VERSION 5.7 ;
  NOWIREEXTENSIONATPIN ON ;
  DIVIDERCHAR "/" ;
  BUSBITCHARS "[]" ;
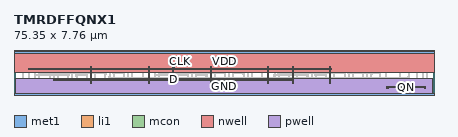
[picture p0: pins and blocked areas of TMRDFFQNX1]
MACRO TMRDFFQNX1
  CLASS CORE ;
  FOREIGN TMRDFFQNX1 ;
  ORIGIN 0.000 0.000 ;
  SIZE 75.350 BY 7.760 ;
  SYMMETRY X Y ;
  SITE unitrh ;
  PIN QN
    DIRECTION OUTPUT ;
    USE SIGNAL ;
    ANTENNADIFFAREA 1.734950 ;
    PORT
      LAYER met1 ;
        RECT 66.905 1.445 67.135 1.475 ;
        RECT 70.235 1.445 70.465 1.475 ;
        RECT 73.565 1.445 73.795 1.475 ;
        RECT 66.875 1.275 73.825 1.445 ;
        RECT 66.905 1.245 67.135 1.275 ;
        RECT 70.235 1.245 70.465 1.275 ;
        RECT 73.565 1.245 73.795 1.275 ;
    END
  END QN
  PIN D
    DIRECTION INPUT ;
    USE SIGNAL ;
    ANTENNAGATEAREA 3.081750 ;
    PORT
      LAYER met1 ;
        RECT 7.035 2.855 7.265 2.885 ;
        RECT 28.495 2.855 28.725 2.885 ;
        RECT 49.955 2.855 50.185 2.885 ;
        RECT 7.005 2.685 50.215 2.855 ;
        RECT 7.035 2.655 7.265 2.685 ;
        RECT 28.495 2.655 28.725 2.685 ;
        RECT 49.955 2.655 50.185 2.685 ;
    END
    PORT
      LAYER li1 ;
        RECT 28.555 4.890 28.725 5.045 ;
        RECT 28.525 4.715 28.725 4.890 ;
        RECT 28.525 2.095 28.695 4.715 ;
      LAYER mcon ;
        RECT 28.525 2.685 28.695 2.855 ;
    END
    PORT
      LAYER li1 ;
        RECT 50.015 4.890 50.185 5.045 ;
        RECT 49.985 4.715 50.185 4.890 ;
        RECT 49.985 2.095 50.155 4.715 ;
      LAYER mcon ;
        RECT 49.985 2.685 50.155 2.855 ;
    END
  END D
  PIN CLK
    DIRECTION INPUT ;
    USE SIGNAL ;
    ANTENNAGATEAREA 6.126300 ;
    PORT
      LAYER met1 ;
        RECT 2.595 4.705 2.825 4.735 ;
        RECT 13.695 4.705 13.925 4.735 ;
        RECT 24.055 4.705 24.285 4.735 ;
        RECT 35.155 4.705 35.385 4.735 ;
        RECT 45.515 4.705 45.745 4.735 ;
        RECT 56.615 4.705 56.845 4.735 ;
        RECT 2.565 4.700 13.955 4.705 ;
        RECT 17.235 4.700 56.875 4.705 ;
        RECT 2.565 4.545 56.875 4.700 ;
        RECT 2.565 4.535 13.955 4.545 ;
        RECT 17.235 4.535 56.875 4.545 ;
        RECT 2.595 4.505 2.825 4.535 ;
        RECT 13.695 4.505 13.925 4.535 ;
        RECT 24.055 4.505 24.285 4.535 ;
        RECT 35.155 4.505 35.385 4.535 ;
        RECT 45.515 4.505 45.745 4.535 ;
        RECT 56.615 4.505 56.845 4.535 ;
    END
    PORT
      LAYER li1 ;
        RECT 13.755 4.890 13.925 5.045 ;
        RECT 13.725 4.715 13.925 4.890 ;
        RECT 13.725 2.095 13.895 4.715 ;
      LAYER mcon ;
        RECT 13.725 4.535 13.895 4.705 ;
    END
    PORT
      LAYER li1 ;
        RECT 24.085 2.095 24.255 5.045 ;
      LAYER mcon ;
        RECT 24.085 4.535 24.255 4.705 ;
    END
    PORT
      LAYER li1 ;
        RECT 35.215 4.890 35.385 5.045 ;
        RECT 35.185 4.715 35.385 4.890 ;
        RECT 35.185 2.095 35.355 4.715 ;
      LAYER mcon ;
        RECT 35.185 4.535 35.355 4.705 ;
    END
    PORT
      LAYER li1 ;
        RECT 45.545 2.095 45.715 5.045 ;
      LAYER mcon ;
        RECT 45.545 4.535 45.715 4.705 ;
    END
    PORT
      LAYER li1 ;
        RECT 56.675 4.890 56.845 5.045 ;
        RECT 56.645 4.715 56.845 4.890 ;
        RECT 56.645 2.095 56.815 4.715 ;
      LAYER mcon ;
        RECT 56.645 4.535 56.815 4.705 ;
    END
  END CLK
  PIN VDD
    DIRECTION INOUT ;
    USE POWER ;
    SHAPE ABUTMENT ;
    PORT
      LAYER nwell ;
        RECT 0.000 4.110 75.350 7.940 ;
      LAYER met1 ;
        RECT 0.000 7.410 75.350 7.760 ;
    END
  END VDD
  PIN GND
    DIRECTION INOUT ;
    USE POWER ;
    SHAPE ABUTMENT ;
    PORT
      LAYER pwell ;
        RECT 0.320 0.000 75.030 2.900 ;
      LAYER met1 ;
        RECT 0.000 0.000 75.350 0.350 ;
    END
  END GND
  OBS
      LAYER li1 ;
        RECT 0.000 7.410 75.350 7.760 ;
        RECT 0.320 4.290 0.660 7.410 ;
        RECT 1.495 5.395 1.665 7.410 ;
        RECT 1.935 5.420 2.105 7.200 ;
        RECT 2.375 5.735 2.545 7.410 ;
        RECT 2.815 5.420 2.985 7.200 ;
        RECT 3.255 5.735 3.425 7.410 ;
        RECT 3.695 5.420 3.865 7.200 ;
        RECT 4.135 5.735 4.305 7.410 ;
        RECT 1.935 5.250 4.645 5.420 ;
        RECT 0.320 0.350 0.660 2.900 ;
        RECT 1.515 2.095 1.685 5.045 ;
        RECT 2.625 2.095 2.795 5.045 ;
        RECT 3.735 2.095 3.905 5.045 ;
        RECT 0.995 1.855 1.165 1.935 ;
        RECT 1.965 1.855 2.135 1.935 ;
        RECT 2.935 1.855 3.105 1.935 ;
        RECT 0.995 1.685 3.105 1.855 ;
        RECT 0.995 0.555 1.165 1.685 ;
        RECT 1.480 0.350 1.650 1.310 ;
        RECT 1.965 0.805 2.135 1.685 ;
        RECT 2.935 1.605 3.105 1.685 ;
        RECT 2.455 1.260 2.625 1.340 ;
        RECT 3.505 1.260 3.675 1.935 ;
        RECT 4.475 1.930 4.645 5.250 ;
        RECT 5.130 4.290 5.470 7.410 ;
        RECT 6.005 5.315 6.175 7.410 ;
        RECT 6.445 5.465 6.615 7.200 ;
        RECT 6.885 5.735 7.055 7.410 ;
        RECT 7.325 5.465 7.495 7.200 ;
        RECT 7.765 5.735 7.935 7.410 ;
        RECT 6.445 5.295 7.975 5.465 ;
        RECT 2.455 1.090 3.675 1.260 ;
        RECT 2.455 1.010 2.625 1.090 ;
        RECT 2.935 0.805 3.105 0.885 ;
        RECT 1.965 0.635 3.105 0.805 ;
        RECT 1.965 0.555 2.135 0.635 ;
        RECT 2.935 0.555 3.105 0.635 ;
        RECT 3.505 0.805 3.675 1.090 ;
        RECT 3.990 1.760 4.645 1.930 ;
        RECT 3.990 1.025 4.160 1.760 ;
        RECT 4.475 0.805 4.645 1.575 ;
        RECT 3.505 0.635 4.645 0.805 ;
        RECT 3.505 0.555 3.675 0.635 ;
        RECT 4.475 0.555 4.645 0.635 ;
        RECT 5.130 0.350 5.470 2.900 ;
        RECT 6.325 2.095 6.495 5.045 ;
        RECT 7.095 4.890 7.265 5.045 ;
        RECT 7.065 4.715 7.265 4.890 ;
        RECT 7.065 2.095 7.235 4.715 ;
        RECT 5.910 1.845 6.080 1.925 ;
        RECT 6.880 1.845 7.050 1.925 ;
        RECT 7.805 1.920 7.975 5.295 ;
        RECT 8.460 4.290 8.800 7.410 ;
        RECT 9.335 5.315 9.505 7.410 ;
        RECT 9.775 5.465 9.945 7.200 ;
        RECT 10.215 5.735 10.385 7.410 ;
        RECT 10.655 5.465 10.825 7.200 ;
        RECT 11.095 5.735 11.265 7.410 ;
        RECT 9.775 5.295 11.305 5.465 ;
        RECT 5.910 1.675 7.050 1.845 ;
        RECT 5.910 0.545 6.080 1.675 ;
        RECT 6.395 0.350 6.565 1.300 ;
        RECT 6.880 0.795 7.050 1.675 ;
        RECT 7.365 1.750 7.975 1.920 ;
        RECT 7.365 1.015 7.535 1.750 ;
        RECT 7.850 0.795 8.020 1.565 ;
        RECT 6.880 0.625 8.020 0.795 ;
        RECT 6.880 0.545 7.050 0.625 ;
        RECT 7.850 0.545 8.020 0.625 ;
        RECT 8.460 0.350 8.800 2.900 ;
        RECT 9.655 2.095 9.825 5.045 ;
        RECT 10.425 4.890 10.595 5.045 ;
        RECT 10.395 4.715 10.595 4.890 ;
        RECT 10.395 2.095 10.565 4.715 ;
        RECT 9.240 1.845 9.410 1.925 ;
        RECT 10.210 1.845 10.380 1.925 ;
        RECT 11.135 1.920 11.305 5.295 ;
        RECT 11.790 4.290 12.130 7.410 ;
        RECT 12.665 5.315 12.835 7.410 ;
        RECT 13.105 5.465 13.275 7.200 ;
        RECT 13.545 5.735 13.715 7.410 ;
        RECT 13.985 5.465 14.155 7.200 ;
        RECT 14.425 5.735 14.595 7.410 ;
        RECT 13.105 5.295 14.635 5.465 ;
        RECT 9.240 1.675 10.380 1.845 ;
        RECT 9.240 0.545 9.410 1.675 ;
        RECT 9.725 0.350 9.895 1.300 ;
        RECT 10.210 0.795 10.380 1.675 ;
        RECT 10.695 1.750 11.305 1.920 ;
        RECT 10.695 1.015 10.865 1.750 ;
        RECT 11.180 0.795 11.350 1.565 ;
        RECT 10.210 0.625 11.350 0.795 ;
        RECT 10.210 0.545 10.380 0.625 ;
        RECT 11.180 0.545 11.350 0.625 ;
        RECT 11.790 0.350 12.130 2.900 ;
        RECT 12.985 2.095 13.155 5.045 ;
        RECT 12.570 1.845 12.740 1.925 ;
        RECT 13.540 1.845 13.710 1.925 ;
        RECT 14.465 1.920 14.635 5.295 ;
        RECT 15.120 4.290 15.460 7.410 ;
        RECT 15.995 5.315 16.165 7.410 ;
        RECT 16.435 5.465 16.605 7.200 ;
        RECT 16.875 5.735 17.045 7.410 ;
        RECT 17.315 5.465 17.485 7.200 ;
        RECT 17.755 5.735 17.925 7.410 ;
        RECT 16.435 5.295 17.965 5.465 ;
        RECT 12.570 1.675 13.710 1.845 ;
        RECT 12.570 0.545 12.740 1.675 ;
        RECT 13.055 0.350 13.225 1.300 ;
        RECT 13.540 0.795 13.710 1.675 ;
        RECT 14.025 1.750 14.635 1.920 ;
        RECT 14.025 1.015 14.195 1.750 ;
        RECT 14.510 0.795 14.680 1.565 ;
        RECT 13.540 0.625 14.680 0.795 ;
        RECT 13.540 0.545 13.710 0.625 ;
        RECT 14.510 0.545 14.680 0.625 ;
        RECT 15.120 0.350 15.460 2.900 ;
        RECT 16.315 2.095 16.485 5.045 ;
        RECT 17.085 4.890 17.255 5.045 ;
        RECT 17.055 4.715 17.255 4.890 ;
        RECT 17.055 2.095 17.225 4.715 ;
        RECT 15.900 1.845 16.070 1.925 ;
        RECT 16.870 1.845 17.040 1.925 ;
        RECT 17.795 1.920 17.965 5.295 ;
        RECT 18.450 4.290 18.790 7.410 ;
        RECT 19.325 5.315 19.495 7.410 ;
        RECT 19.765 5.465 19.935 7.200 ;
        RECT 20.205 5.735 20.375 7.410 ;
        RECT 20.645 5.465 20.815 7.200 ;
        RECT 21.085 5.735 21.255 7.410 ;
        RECT 19.765 5.295 21.295 5.465 ;
        RECT 15.900 1.675 17.040 1.845 ;
        RECT 15.900 0.545 16.070 1.675 ;
        RECT 16.385 0.350 16.555 1.300 ;
        RECT 16.870 0.795 17.040 1.675 ;
        RECT 17.355 1.750 17.965 1.920 ;
        RECT 17.355 1.015 17.525 1.750 ;
        RECT 17.840 0.795 18.010 1.565 ;
        RECT 16.870 0.625 18.010 0.795 ;
        RECT 16.870 0.545 17.040 0.625 ;
        RECT 17.840 0.545 18.010 0.625 ;
        RECT 18.450 0.350 18.790 2.900 ;
        RECT 19.645 2.095 19.815 5.045 ;
        RECT 20.415 4.890 20.585 5.045 ;
        RECT 20.385 4.715 20.585 4.890 ;
        RECT 20.385 2.095 20.555 4.715 ;
        RECT 19.230 1.845 19.400 1.925 ;
        RECT 20.200 1.845 20.370 1.925 ;
        RECT 21.125 1.920 21.295 5.295 ;
        RECT 21.780 4.290 22.120 7.410 ;
        RECT 22.955 5.395 23.125 7.410 ;
        RECT 23.395 5.420 23.565 7.200 ;
        RECT 23.835 5.735 24.005 7.410 ;
        RECT 24.275 5.420 24.445 7.200 ;
        RECT 24.715 5.735 24.885 7.410 ;
        RECT 25.155 5.420 25.325 7.200 ;
        RECT 25.595 5.735 25.765 7.410 ;
        RECT 23.395 5.250 26.105 5.420 ;
        RECT 19.230 1.675 20.370 1.845 ;
        RECT 19.230 0.545 19.400 1.675 ;
        RECT 19.715 0.350 19.885 1.300 ;
        RECT 20.200 0.795 20.370 1.675 ;
        RECT 20.685 1.750 21.295 1.920 ;
        RECT 20.685 1.015 20.855 1.750 ;
        RECT 21.170 0.795 21.340 1.565 ;
        RECT 20.200 0.625 21.340 0.795 ;
        RECT 20.200 0.545 20.370 0.625 ;
        RECT 21.170 0.545 21.340 0.625 ;
        RECT 21.780 0.350 22.120 2.900 ;
        RECT 22.975 2.095 23.145 5.045 ;
        RECT 25.195 2.095 25.365 5.045 ;
        RECT 22.455 1.855 22.625 1.935 ;
        RECT 23.425 1.855 23.595 1.935 ;
        RECT 24.395 1.855 24.565 1.935 ;
        RECT 22.455 1.685 24.565 1.855 ;
        RECT 22.455 0.555 22.625 1.685 ;
        RECT 22.940 0.350 23.110 1.310 ;
        RECT 23.425 0.805 23.595 1.685 ;
        RECT 24.395 1.605 24.565 1.685 ;
        RECT 23.915 1.260 24.085 1.340 ;
        RECT 24.965 1.260 25.135 1.935 ;
        RECT 25.935 1.930 26.105 5.250 ;
        RECT 26.590 4.290 26.930 7.410 ;
        RECT 27.465 5.315 27.635 7.410 ;
        RECT 27.905 5.465 28.075 7.200 ;
        RECT 28.345 5.735 28.515 7.410 ;
        RECT 28.785 5.465 28.955 7.200 ;
        RECT 29.225 5.735 29.395 7.410 ;
        RECT 27.905 5.295 29.435 5.465 ;
        RECT 23.915 1.090 25.135 1.260 ;
        RECT 23.915 1.010 24.085 1.090 ;
        RECT 24.395 0.805 24.565 0.885 ;
        RECT 23.425 0.635 24.565 0.805 ;
        RECT 23.425 0.555 23.595 0.635 ;
        RECT 24.395 0.555 24.565 0.635 ;
        RECT 24.965 0.805 25.135 1.090 ;
        RECT 25.450 1.760 26.105 1.930 ;
        RECT 25.450 1.025 25.620 1.760 ;
        RECT 25.935 0.805 26.105 1.575 ;
        RECT 24.965 0.635 26.105 0.805 ;
        RECT 24.965 0.555 25.135 0.635 ;
        RECT 25.935 0.555 26.105 0.635 ;
        RECT 26.590 0.350 26.930 2.900 ;
        RECT 27.785 2.095 27.955 5.045 ;
        RECT 27.370 1.845 27.540 1.925 ;
        RECT 28.340 1.845 28.510 1.925 ;
        RECT 29.265 1.920 29.435 5.295 ;
        RECT 29.920 4.290 30.260 7.410 ;
        RECT 30.795 5.315 30.965 7.410 ;
        RECT 31.235 5.465 31.405 7.200 ;
        RECT 31.675 5.735 31.845 7.410 ;
        RECT 32.115 5.465 32.285 7.200 ;
        RECT 32.555 5.735 32.725 7.410 ;
        RECT 31.235 5.295 32.765 5.465 ;
        RECT 27.370 1.675 28.510 1.845 ;
        RECT 27.370 0.545 27.540 1.675 ;
        RECT 27.855 0.350 28.025 1.300 ;
        RECT 28.340 0.795 28.510 1.675 ;
        RECT 28.825 1.750 29.435 1.920 ;
        RECT 28.825 1.015 28.995 1.750 ;
        RECT 29.310 0.795 29.480 1.565 ;
        RECT 28.340 0.625 29.480 0.795 ;
        RECT 28.340 0.545 28.510 0.625 ;
        RECT 29.310 0.545 29.480 0.625 ;
        RECT 29.920 0.350 30.260 2.900 ;
        RECT 31.115 2.095 31.285 5.045 ;
        RECT 31.885 4.890 32.055 5.045 ;
        RECT 31.855 4.715 32.055 4.890 ;
        RECT 31.855 2.095 32.025 4.715 ;
        RECT 30.700 1.845 30.870 1.925 ;
        RECT 31.670 1.845 31.840 1.925 ;
        RECT 32.595 1.920 32.765 5.295 ;
        RECT 33.250 4.290 33.590 7.410 ;
        RECT 34.125 5.315 34.295 7.410 ;
        RECT 34.565 5.465 34.735 7.200 ;
        RECT 35.005 5.735 35.175 7.410 ;
        RECT 35.445 5.465 35.615 7.200 ;
        RECT 35.885 5.735 36.055 7.410 ;
        RECT 34.565 5.295 36.095 5.465 ;
        RECT 30.700 1.675 31.840 1.845 ;
        RECT 30.700 0.545 30.870 1.675 ;
        RECT 31.185 0.350 31.355 1.300 ;
        RECT 31.670 0.795 31.840 1.675 ;
        RECT 32.155 1.750 32.765 1.920 ;
        RECT 32.155 1.015 32.325 1.750 ;
        RECT 32.640 0.795 32.810 1.565 ;
        RECT 31.670 0.625 32.810 0.795 ;
        RECT 31.670 0.545 31.840 0.625 ;
        RECT 32.640 0.545 32.810 0.625 ;
        RECT 33.250 0.350 33.590 2.900 ;
        RECT 34.445 2.095 34.615 5.045 ;
        RECT 34.030 1.845 34.200 1.925 ;
        RECT 35.000 1.845 35.170 1.925 ;
        RECT 35.925 1.920 36.095 5.295 ;
        RECT 36.580 4.290 36.920 7.410 ;
        RECT 37.455 5.315 37.625 7.410 ;
        RECT 37.895 5.465 38.065 7.200 ;
        RECT 38.335 5.735 38.505 7.410 ;
        RECT 38.775 5.465 38.945 7.200 ;
        RECT 39.215 5.735 39.385 7.410 ;
        RECT 37.895 5.295 39.425 5.465 ;
        RECT 34.030 1.675 35.170 1.845 ;
        RECT 34.030 0.545 34.200 1.675 ;
        RECT 34.515 0.350 34.685 1.300 ;
        RECT 35.000 0.795 35.170 1.675 ;
        RECT 35.485 1.750 36.095 1.920 ;
        RECT 35.485 1.015 35.655 1.750 ;
        RECT 35.970 0.795 36.140 1.565 ;
        RECT 35.000 0.625 36.140 0.795 ;
        RECT 35.000 0.545 35.170 0.625 ;
        RECT 35.970 0.545 36.140 0.625 ;
        RECT 36.580 0.350 36.920 2.900 ;
        RECT 37.775 2.095 37.945 5.045 ;
        RECT 38.545 4.890 38.715 5.045 ;
        RECT 38.515 4.715 38.715 4.890 ;
        RECT 38.515 2.095 38.685 4.715 ;
        RECT 37.360 1.845 37.530 1.925 ;
        RECT 38.330 1.845 38.500 1.925 ;
        RECT 39.255 1.920 39.425 5.295 ;
        RECT 39.910 4.290 40.250 7.410 ;
        RECT 40.785 5.315 40.955 7.410 ;
        RECT 41.225 5.465 41.395 7.200 ;
        RECT 41.665 5.735 41.835 7.410 ;
        RECT 42.105 5.465 42.275 7.200 ;
        RECT 42.545 5.735 42.715 7.410 ;
        RECT 41.225 5.295 42.755 5.465 ;
        RECT 37.360 1.675 38.500 1.845 ;
        RECT 37.360 0.545 37.530 1.675 ;
        RECT 37.845 0.350 38.015 1.300 ;
        RECT 38.330 0.795 38.500 1.675 ;
        RECT 38.815 1.750 39.425 1.920 ;
        RECT 38.815 1.015 38.985 1.750 ;
        RECT 39.300 0.795 39.470 1.565 ;
        RECT 38.330 0.625 39.470 0.795 ;
        RECT 38.330 0.545 38.500 0.625 ;
        RECT 39.300 0.545 39.470 0.625 ;
        RECT 39.910 0.350 40.250 2.900 ;
        RECT 41.105 2.095 41.275 5.045 ;
        RECT 41.875 4.890 42.045 5.045 ;
        RECT 41.845 4.715 42.045 4.890 ;
        RECT 41.845 2.095 42.015 4.715 ;
        RECT 40.690 1.845 40.860 1.925 ;
        RECT 41.660 1.845 41.830 1.925 ;
        RECT 42.585 1.920 42.755 5.295 ;
        RECT 43.240 4.290 43.580 7.410 ;
        RECT 44.415 5.395 44.585 7.410 ;
        RECT 44.855 5.420 45.025 7.200 ;
        RECT 45.295 5.735 45.465 7.410 ;
        RECT 45.735 5.420 45.905 7.200 ;
        RECT 46.175 5.735 46.345 7.410 ;
        RECT 46.615 5.420 46.785 7.200 ;
        RECT 47.055 5.735 47.225 7.410 ;
        RECT 44.855 5.250 47.565 5.420 ;
        RECT 40.690 1.675 41.830 1.845 ;
        RECT 40.690 0.545 40.860 1.675 ;
        RECT 41.175 0.350 41.345 1.300 ;
        RECT 41.660 0.795 41.830 1.675 ;
        RECT 42.145 1.750 42.755 1.920 ;
        RECT 42.145 1.015 42.315 1.750 ;
        RECT 42.630 0.795 42.800 1.565 ;
        RECT 41.660 0.625 42.800 0.795 ;
        RECT 41.660 0.545 41.830 0.625 ;
        RECT 42.630 0.545 42.800 0.625 ;
        RECT 43.240 0.350 43.580 2.900 ;
        RECT 44.435 2.095 44.605 5.045 ;
        RECT 46.655 2.095 46.825 5.045 ;
        RECT 43.915 1.855 44.085 1.935 ;
        RECT 44.885 1.855 45.055 1.935 ;
        RECT 45.855 1.855 46.025 1.935 ;
        RECT 43.915 1.685 46.025 1.855 ;
        RECT 43.915 0.555 44.085 1.685 ;
        RECT 44.400 0.350 44.570 1.310 ;
        RECT 44.885 0.805 45.055 1.685 ;
        RECT 45.855 1.605 46.025 1.685 ;
        RECT 45.375 1.260 45.545 1.340 ;
        RECT 46.425 1.260 46.595 1.935 ;
        RECT 47.395 1.930 47.565 5.250 ;
        RECT 48.050 4.290 48.390 7.410 ;
        RECT 48.925 5.315 49.095 7.410 ;
        RECT 49.365 5.465 49.535 7.200 ;
        RECT 49.805 5.735 49.975 7.410 ;
        RECT 50.245 5.465 50.415 7.200 ;
        RECT 50.685 5.735 50.855 7.410 ;
        RECT 49.365 5.295 50.895 5.465 ;
        RECT 45.375 1.090 46.595 1.260 ;
        RECT 45.375 1.010 45.545 1.090 ;
        RECT 45.855 0.805 46.025 0.885 ;
        RECT 44.885 0.635 46.025 0.805 ;
        RECT 44.885 0.555 45.055 0.635 ;
        RECT 45.855 0.555 46.025 0.635 ;
        RECT 46.425 0.805 46.595 1.090 ;
        RECT 46.910 1.760 47.565 1.930 ;
        RECT 46.910 1.025 47.080 1.760 ;
        RECT 47.395 0.805 47.565 1.575 ;
        RECT 46.425 0.635 47.565 0.805 ;
        RECT 46.425 0.555 46.595 0.635 ;
        RECT 47.395 0.555 47.565 0.635 ;
        RECT 48.050 0.350 48.390 2.900 ;
        RECT 49.245 2.095 49.415 5.045 ;
        RECT 48.830 1.845 49.000 1.925 ;
        RECT 49.800 1.845 49.970 1.925 ;
        RECT 50.725 1.920 50.895 5.295 ;
        RECT 51.380 4.290 51.720 7.410 ;
        RECT 52.255 5.315 52.425 7.410 ;
        RECT 52.695 5.465 52.865 7.200 ;
        RECT 53.135 5.735 53.305 7.410 ;
        RECT 53.575 5.465 53.745 7.200 ;
        RECT 54.015 5.735 54.185 7.410 ;
        RECT 52.695 5.295 54.225 5.465 ;
        RECT 48.830 1.675 49.970 1.845 ;
        RECT 48.830 0.545 49.000 1.675 ;
        RECT 49.315 0.350 49.485 1.300 ;
        RECT 49.800 0.795 49.970 1.675 ;
        RECT 50.285 1.750 50.895 1.920 ;
        RECT 50.285 1.015 50.455 1.750 ;
        RECT 50.770 0.795 50.940 1.565 ;
        RECT 49.800 0.625 50.940 0.795 ;
        RECT 49.800 0.545 49.970 0.625 ;
        RECT 50.770 0.545 50.940 0.625 ;
        RECT 51.380 0.350 51.720 2.900 ;
        RECT 52.575 2.095 52.745 5.045 ;
        RECT 53.345 4.890 53.515 5.045 ;
        RECT 53.315 4.715 53.515 4.890 ;
        RECT 53.315 2.095 53.485 4.715 ;
        RECT 52.160 1.845 52.330 1.925 ;
        RECT 53.130 1.845 53.300 1.925 ;
        RECT 54.055 1.920 54.225 5.295 ;
        RECT 54.710 4.290 55.050 7.410 ;
        RECT 55.585 5.315 55.755 7.410 ;
        RECT 56.025 5.465 56.195 7.200 ;
        RECT 56.465 5.735 56.635 7.410 ;
        RECT 56.905 5.465 57.075 7.200 ;
        RECT 57.345 5.735 57.515 7.410 ;
        RECT 56.025 5.295 57.555 5.465 ;
        RECT 52.160 1.675 53.300 1.845 ;
        RECT 52.160 0.545 52.330 1.675 ;
        RECT 52.645 0.350 52.815 1.300 ;
        RECT 53.130 0.795 53.300 1.675 ;
        RECT 53.615 1.750 54.225 1.920 ;
        RECT 53.615 1.015 53.785 1.750 ;
        RECT 54.100 0.795 54.270 1.565 ;
        RECT 53.130 0.625 54.270 0.795 ;
        RECT 53.130 0.545 53.300 0.625 ;
        RECT 54.100 0.545 54.270 0.625 ;
        RECT 54.710 0.350 55.050 2.900 ;
        RECT 55.905 2.095 56.075 5.045 ;
        RECT 55.490 1.845 55.660 1.925 ;
        RECT 56.460 1.845 56.630 1.925 ;
        RECT 57.385 1.920 57.555 5.295 ;
        RECT 58.040 4.290 58.380 7.410 ;
        RECT 58.915 5.315 59.085 7.410 ;
        RECT 59.355 5.465 59.525 7.200 ;
        RECT 59.795 5.735 59.965 7.410 ;
        RECT 60.235 5.465 60.405 7.200 ;
        RECT 60.675 5.735 60.845 7.410 ;
        RECT 59.355 5.295 60.885 5.465 ;
        RECT 55.490 1.675 56.630 1.845 ;
        RECT 55.490 0.545 55.660 1.675 ;
        RECT 55.975 0.350 56.145 1.300 ;
        RECT 56.460 0.795 56.630 1.675 ;
        RECT 56.945 1.750 57.555 1.920 ;
        RECT 56.945 1.015 57.115 1.750 ;
        RECT 57.430 0.795 57.600 1.565 ;
        RECT 56.460 0.625 57.600 0.795 ;
        RECT 56.460 0.545 56.630 0.625 ;
        RECT 57.430 0.545 57.600 0.625 ;
        RECT 58.040 0.350 58.380 2.900 ;
        RECT 59.235 2.095 59.405 5.045 ;
        RECT 60.005 4.890 60.175 5.045 ;
        RECT 59.975 4.715 60.175 4.890 ;
        RECT 59.975 2.095 60.145 4.715 ;
        RECT 58.820 1.845 58.990 1.925 ;
        RECT 59.790 1.845 59.960 1.925 ;
        RECT 60.715 1.920 60.885 5.295 ;
        RECT 61.370 4.290 61.710 7.410 ;
        RECT 62.245 5.315 62.415 7.410 ;
        RECT 62.685 5.465 62.855 7.200 ;
        RECT 63.125 5.735 63.295 7.410 ;
        RECT 63.565 5.465 63.735 7.200 ;
        RECT 64.005 5.735 64.175 7.410 ;
        RECT 62.685 5.295 64.215 5.465 ;
        RECT 58.820 1.675 59.960 1.845 ;
        RECT 58.820 0.545 58.990 1.675 ;
        RECT 59.305 0.350 59.475 1.300 ;
        RECT 59.790 0.795 59.960 1.675 ;
        RECT 60.275 1.750 60.885 1.920 ;
        RECT 60.275 1.015 60.445 1.750 ;
        RECT 60.760 0.795 60.930 1.565 ;
        RECT 59.790 0.625 60.930 0.795 ;
        RECT 59.790 0.545 59.960 0.625 ;
        RECT 60.760 0.545 60.930 0.625 ;
        RECT 61.370 0.350 61.710 2.900 ;
        RECT 62.565 2.095 62.735 5.045 ;
        RECT 63.335 4.890 63.505 5.045 ;
        RECT 63.305 4.715 63.505 4.890 ;
        RECT 63.305 2.095 63.475 4.715 ;
        RECT 62.150 1.845 62.320 1.925 ;
        RECT 63.120 1.845 63.290 1.925 ;
        RECT 64.045 1.920 64.215 5.295 ;
        RECT 64.700 4.290 65.040 7.410 ;
        RECT 65.575 5.305 65.745 7.410 ;
        RECT 66.015 7.005 66.195 7.175 ;
        RECT 66.015 5.475 66.185 7.005 ;
        RECT 66.455 5.735 66.625 7.410 ;
        RECT 66.895 5.475 67.065 7.175 ;
        RECT 66.015 5.305 67.065 5.475 ;
        RECT 67.335 5.305 67.505 7.410 ;
        RECT 66.895 5.225 67.065 5.305 ;
        RECT 62.150 1.675 63.290 1.845 ;
        RECT 62.150 0.545 62.320 1.675 ;
        RECT 62.635 0.350 62.805 1.300 ;
        RECT 63.120 0.795 63.290 1.675 ;
        RECT 63.605 1.750 64.215 1.920 ;
        RECT 63.605 1.015 63.775 1.750 ;
        RECT 64.090 0.795 64.260 1.565 ;
        RECT 63.120 0.625 64.260 0.795 ;
        RECT 63.120 0.545 63.290 0.625 ;
        RECT 64.090 0.545 64.260 0.625 ;
        RECT 64.700 0.350 65.040 2.900 ;
        RECT 65.525 2.095 65.695 5.050 ;
        RECT 66.675 4.890 66.845 5.050 ;
        RECT 66.635 4.720 66.845 4.890 ;
        RECT 66.635 2.095 66.805 4.720 ;
        RECT 68.030 4.290 68.370 7.410 ;
        RECT 68.895 7.005 70.825 7.175 ;
        RECT 68.895 5.225 69.065 7.005 ;
        RECT 69.335 5.475 69.505 6.745 ;
        RECT 69.775 5.735 69.945 7.005 ;
        RECT 70.215 5.475 70.385 6.745 ;
        RECT 70.655 5.555 70.825 7.005 ;
        RECT 69.335 5.305 70.385 5.475 ;
        RECT 70.215 5.225 70.385 5.305 ;
        RECT 65.480 1.845 65.650 1.925 ;
        RECT 66.450 1.845 66.620 1.925 ;
        RECT 65.480 1.675 66.620 1.845 ;
        RECT 65.480 0.545 65.650 1.675 ;
        RECT 65.965 0.350 66.135 1.300 ;
        RECT 66.450 0.795 66.620 1.675 ;
        RECT 66.935 1.350 67.105 1.525 ;
        RECT 66.930 1.195 67.105 1.350 ;
        RECT 66.930 1.015 67.100 1.195 ;
        RECT 67.420 0.795 67.590 1.925 ;
        RECT 66.450 0.625 67.590 0.795 ;
        RECT 66.450 0.545 66.620 0.625 ;
        RECT 67.420 0.545 67.590 0.625 ;
        RECT 68.030 0.350 68.370 2.900 ;
        RECT 69.225 2.095 69.395 5.050 ;
        RECT 70.705 2.095 70.875 5.050 ;
        RECT 71.360 4.290 71.700 7.410 ;
        RECT 72.235 7.005 74.165 7.175 ;
        RECT 72.235 5.225 72.405 7.005 ;
        RECT 72.675 5.475 72.845 6.745 ;
        RECT 73.115 5.735 73.285 7.005 ;
        RECT 73.555 5.475 73.725 6.745 ;
        RECT 73.995 5.735 74.165 7.005 ;
        RECT 72.675 5.305 74.205 5.475 ;
        RECT 68.810 1.845 68.980 1.925 ;
        RECT 69.780 1.845 69.950 1.925 ;
        RECT 68.810 1.675 69.950 1.845 ;
        RECT 68.810 0.545 68.980 1.675 ;
        RECT 69.295 0.350 69.465 1.300 ;
        RECT 69.780 0.795 69.950 1.675 ;
        RECT 70.265 1.015 70.435 1.525 ;
        RECT 70.750 0.795 70.920 1.925 ;
        RECT 69.780 0.625 70.920 0.795 ;
        RECT 69.780 0.545 69.950 0.625 ;
        RECT 70.750 0.545 70.920 0.625 ;
        RECT 71.360 0.350 71.700 2.900 ;
        RECT 72.185 2.095 72.355 5.050 ;
        RECT 73.295 4.720 73.485 5.050 ;
        RECT 73.295 2.095 73.465 4.720 ;
        RECT 72.140 1.845 72.310 1.925 ;
        RECT 73.110 1.845 73.280 1.925 ;
        RECT 74.035 1.910 74.205 5.305 ;
        RECT 74.690 4.290 75.030 7.410 ;
        RECT 72.140 1.675 73.280 1.845 ;
        RECT 72.140 0.545 72.310 1.675 ;
        RECT 72.625 0.350 72.795 1.300 ;
        RECT 73.110 0.795 73.280 1.675 ;
        RECT 73.595 1.740 74.205 1.910 ;
        RECT 73.595 1.015 73.765 1.740 ;
        RECT 74.080 0.795 74.250 1.570 ;
        RECT 73.110 0.625 74.250 0.795 ;
        RECT 73.110 0.545 73.280 0.625 ;
        RECT 74.080 0.545 74.250 0.625 ;
        RECT 74.690 0.350 75.030 2.900 ;
        RECT 0.000 0.000 75.350 0.350 ;
      LAYER mcon ;
        RECT 0.775 7.495 0.945 7.665 ;
        RECT 1.145 7.495 1.315 7.665 ;
        RECT 1.515 7.495 1.685 7.665 ;
        RECT 1.885 7.495 2.055 7.665 ;
        RECT 2.255 7.495 2.425 7.665 ;
        RECT 2.625 7.495 2.795 7.665 ;
        RECT 2.995 7.495 3.165 7.665 ;
        RECT 3.365 7.495 3.535 7.665 ;
        RECT 3.735 7.495 3.905 7.665 ;
        RECT 4.105 7.495 4.275 7.665 ;
        RECT 4.475 7.495 4.645 7.665 ;
        RECT 4.845 7.495 5.015 7.665 ;
        RECT 5.585 7.495 5.755 7.665 ;
        RECT 5.955 7.495 6.125 7.665 ;
        RECT 6.325 7.495 6.495 7.665 ;
        RECT 6.695 7.495 6.865 7.665 ;
        RECT 7.065 7.495 7.235 7.665 ;
        RECT 7.435 7.495 7.605 7.665 ;
        RECT 7.805 7.495 7.975 7.665 ;
        RECT 8.175 7.495 8.345 7.665 ;
        RECT 8.915 7.495 9.085 7.665 ;
        RECT 9.285 7.495 9.455 7.665 ;
        RECT 9.655 7.495 9.825 7.665 ;
        RECT 10.025 7.495 10.195 7.665 ;
        RECT 10.395 7.495 10.565 7.665 ;
        RECT 10.765 7.495 10.935 7.665 ;
        RECT 11.135 7.495 11.305 7.665 ;
        RECT 11.505 7.495 11.675 7.665 ;
        RECT 12.245 7.495 12.415 7.665 ;
        RECT 12.615 7.495 12.785 7.665 ;
        RECT 12.985 7.495 13.155 7.665 ;
        RECT 13.355 7.495 13.525 7.665 ;
        RECT 13.725 7.495 13.895 7.665 ;
        RECT 14.095 7.495 14.265 7.665 ;
        RECT 14.465 7.495 14.635 7.665 ;
        RECT 14.835 7.495 15.005 7.665 ;
        RECT 15.575 7.495 15.745 7.665 ;
        RECT 15.945 7.495 16.115 7.665 ;
        RECT 16.315 7.495 16.485 7.665 ;
        RECT 16.685 7.495 16.855 7.665 ;
        RECT 17.055 7.495 17.225 7.665 ;
        RECT 17.425 7.495 17.595 7.665 ;
        RECT 17.795 7.495 17.965 7.665 ;
        RECT 18.165 7.495 18.335 7.665 ;
        RECT 18.905 7.495 19.075 7.665 ;
        RECT 19.275 7.495 19.445 7.665 ;
        RECT 19.645 7.495 19.815 7.665 ;
        RECT 20.015 7.495 20.185 7.665 ;
        RECT 20.385 7.495 20.555 7.665 ;
        RECT 20.755 7.495 20.925 7.665 ;
        RECT 21.125 7.495 21.295 7.665 ;
        RECT 21.495 7.495 21.665 7.665 ;
        RECT 22.235 7.495 22.405 7.665 ;
        RECT 22.605 7.495 22.775 7.665 ;
        RECT 22.975 7.495 23.145 7.665 ;
        RECT 23.345 7.495 23.515 7.665 ;
        RECT 23.715 7.495 23.885 7.665 ;
        RECT 24.085 7.495 24.255 7.665 ;
        RECT 24.455 7.495 24.625 7.665 ;
        RECT 24.825 7.495 24.995 7.665 ;
        RECT 25.195 7.495 25.365 7.665 ;
        RECT 25.565 7.495 25.735 7.665 ;
        RECT 25.935 7.495 26.105 7.665 ;
        RECT 26.305 7.495 26.475 7.665 ;
        RECT 27.045 7.495 27.215 7.665 ;
        RECT 27.415 7.495 27.585 7.665 ;
        RECT 27.785 7.495 27.955 7.665 ;
        RECT 28.155 7.495 28.325 7.665 ;
        RECT 28.525 7.495 28.695 7.665 ;
        RECT 28.895 7.495 29.065 7.665 ;
        RECT 29.265 7.495 29.435 7.665 ;
        RECT 29.635 7.495 29.805 7.665 ;
        RECT 30.375 7.495 30.545 7.665 ;
        RECT 30.745 7.495 30.915 7.665 ;
        RECT 31.115 7.495 31.285 7.665 ;
        RECT 31.485 7.495 31.655 7.665 ;
        RECT 31.855 7.495 32.025 7.665 ;
        RECT 32.225 7.495 32.395 7.665 ;
        RECT 32.595 7.495 32.765 7.665 ;
        RECT 32.965 7.495 33.135 7.665 ;
        RECT 33.705 7.495 33.875 7.665 ;
        RECT 34.075 7.495 34.245 7.665 ;
        RECT 34.445 7.495 34.615 7.665 ;
        RECT 34.815 7.495 34.985 7.665 ;
        RECT 35.185 7.495 35.355 7.665 ;
        RECT 35.555 7.495 35.725 7.665 ;
        RECT 35.925 7.495 36.095 7.665 ;
        RECT 36.295 7.495 36.465 7.665 ;
        RECT 37.035 7.495 37.205 7.665 ;
        RECT 37.405 7.495 37.575 7.665 ;
        RECT 37.775 7.495 37.945 7.665 ;
        RECT 38.145 7.495 38.315 7.665 ;
        RECT 38.515 7.495 38.685 7.665 ;
        RECT 38.885 7.495 39.055 7.665 ;
        RECT 39.255 7.495 39.425 7.665 ;
        RECT 39.625 7.495 39.795 7.665 ;
        RECT 40.365 7.495 40.535 7.665 ;
        RECT 40.735 7.495 40.905 7.665 ;
        RECT 41.105 7.495 41.275 7.665 ;
        RECT 41.475 7.495 41.645 7.665 ;
        RECT 41.845 7.495 42.015 7.665 ;
        RECT 42.215 7.495 42.385 7.665 ;
        RECT 42.585 7.495 42.755 7.665 ;
        RECT 42.955 7.495 43.125 7.665 ;
        RECT 43.695 7.495 43.865 7.665 ;
        RECT 44.065 7.495 44.235 7.665 ;
        RECT 44.435 7.495 44.605 7.665 ;
        RECT 44.805 7.495 44.975 7.665 ;
        RECT 45.175 7.495 45.345 7.665 ;
        RECT 45.545 7.495 45.715 7.665 ;
        RECT 45.915 7.495 46.085 7.665 ;
        RECT 46.285 7.495 46.455 7.665 ;
        RECT 46.655 7.495 46.825 7.665 ;
        RECT 47.025 7.495 47.195 7.665 ;
        RECT 47.395 7.495 47.565 7.665 ;
        RECT 47.765 7.495 47.935 7.665 ;
        RECT 48.505 7.495 48.675 7.665 ;
        RECT 48.875 7.495 49.045 7.665 ;
        RECT 49.245 7.495 49.415 7.665 ;
        RECT 49.615 7.495 49.785 7.665 ;
        RECT 49.985 7.495 50.155 7.665 ;
        RECT 50.355 7.495 50.525 7.665 ;
        RECT 50.725 7.495 50.895 7.665 ;
        RECT 51.095 7.495 51.265 7.665 ;
        RECT 51.835 7.495 52.005 7.665 ;
        RECT 52.205 7.495 52.375 7.665 ;
        RECT 52.575 7.495 52.745 7.665 ;
        RECT 52.945 7.495 53.115 7.665 ;
        RECT 53.315 7.495 53.485 7.665 ;
        RECT 53.685 7.495 53.855 7.665 ;
        RECT 54.055 7.495 54.225 7.665 ;
        RECT 54.425 7.495 54.595 7.665 ;
        RECT 55.165 7.495 55.335 7.665 ;
        RECT 55.535 7.495 55.705 7.665 ;
        RECT 55.905 7.495 56.075 7.665 ;
        RECT 56.275 7.495 56.445 7.665 ;
        RECT 56.645 7.495 56.815 7.665 ;
        RECT 57.015 7.495 57.185 7.665 ;
        RECT 57.385 7.495 57.555 7.665 ;
        RECT 57.755 7.495 57.925 7.665 ;
        RECT 58.495 7.495 58.665 7.665 ;
        RECT 58.865 7.495 59.035 7.665 ;
        RECT 59.235 7.495 59.405 7.665 ;
        RECT 59.605 7.495 59.775 7.665 ;
        RECT 59.975 7.495 60.145 7.665 ;
        RECT 60.345 7.495 60.515 7.665 ;
        RECT 60.715 7.495 60.885 7.665 ;
        RECT 61.085 7.495 61.255 7.665 ;
        RECT 61.825 7.495 61.995 7.665 ;
        RECT 62.195 7.495 62.365 7.665 ;
        RECT 62.565 7.495 62.735 7.665 ;
        RECT 62.935 7.495 63.105 7.665 ;
        RECT 63.305 7.495 63.475 7.665 ;
        RECT 63.675 7.495 63.845 7.665 ;
        RECT 64.045 7.495 64.215 7.665 ;
        RECT 64.415 7.495 64.585 7.665 ;
        RECT 65.155 7.495 65.325 7.665 ;
        RECT 65.525 7.495 65.695 7.665 ;
        RECT 65.895 7.495 66.065 7.665 ;
        RECT 66.265 7.495 66.435 7.665 ;
        RECT 66.635 7.495 66.805 7.665 ;
        RECT 67.005 7.495 67.175 7.665 ;
        RECT 67.375 7.495 67.545 7.665 ;
        RECT 67.745 7.495 67.915 7.665 ;
        RECT 68.485 7.495 68.655 7.665 ;
        RECT 68.855 7.495 69.025 7.665 ;
        RECT 69.225 7.495 69.395 7.665 ;
        RECT 69.595 7.495 69.765 7.665 ;
        RECT 69.965 7.495 70.135 7.665 ;
        RECT 70.335 7.495 70.505 7.665 ;
        RECT 70.705 7.495 70.875 7.665 ;
        RECT 71.075 7.495 71.245 7.665 ;
        RECT 71.815 7.495 71.985 7.665 ;
        RECT 72.185 7.495 72.355 7.665 ;
        RECT 72.555 7.495 72.725 7.665 ;
        RECT 72.925 7.495 73.095 7.665 ;
        RECT 73.295 7.495 73.465 7.665 ;
        RECT 73.665 7.495 73.835 7.665 ;
        RECT 74.035 7.495 74.205 7.665 ;
        RECT 74.405 7.495 74.575 7.665 ;
        RECT 1.515 4.165 1.685 4.335 ;
        RECT 2.625 4.535 2.795 4.705 ;
        RECT 3.735 3.425 3.905 3.595 ;
        RECT 4.475 3.795 4.645 3.965 ;
        RECT 6.325 3.795 6.495 3.965 ;
        RECT 7.065 2.685 7.235 2.855 ;
        RECT 7.805 3.425 7.975 3.595 ;
        RECT 9.655 3.425 9.825 3.595 ;
        RECT 10.395 4.165 10.565 4.335 ;
        RECT 11.135 3.425 11.305 3.595 ;
        RECT 12.985 3.425 13.155 3.595 ;
        RECT 14.465 4.165 14.635 4.335 ;
        RECT 16.315 3.795 16.485 3.965 ;
        RECT 17.055 3.055 17.225 3.225 ;
        RECT 17.795 3.795 17.965 3.965 ;
        RECT 19.645 3.795 19.815 3.965 ;
        RECT 20.385 4.165 20.555 4.335 ;
        RECT 21.125 3.055 21.295 3.225 ;
        RECT 22.975 4.165 23.145 4.335 ;
        RECT 25.195 3.425 25.365 3.595 ;
        RECT 25.935 3.795 26.105 3.965 ;
        RECT 27.785 3.795 27.955 3.965 ;
        RECT 29.265 3.425 29.435 3.595 ;
        RECT 31.115 3.425 31.285 3.595 ;
        RECT 31.855 4.165 32.025 4.335 ;
        RECT 32.595 3.425 32.765 3.595 ;
        RECT 34.445 3.425 34.615 3.595 ;
        RECT 35.925 4.165 36.095 4.335 ;
        RECT 37.775 3.795 37.945 3.965 ;
        RECT 38.515 2.315 38.685 2.485 ;
        RECT 39.255 3.795 39.425 3.965 ;
        RECT 41.105 3.795 41.275 3.965 ;
        RECT 41.845 4.165 42.015 4.335 ;
        RECT 44.435 4.165 44.605 4.335 ;
        RECT 42.585 2.315 42.755 2.485 ;
        RECT 46.655 3.425 46.825 3.595 ;
        RECT 47.395 3.795 47.565 3.965 ;
        RECT 49.245 3.795 49.415 3.965 ;
        RECT 50.725 3.425 50.895 3.595 ;
        RECT 52.575 3.425 52.745 3.595 ;
        RECT 53.315 4.165 53.485 4.335 ;
        RECT 54.055 3.425 54.225 3.595 ;
        RECT 55.905 3.425 56.075 3.595 ;
        RECT 57.385 4.165 57.555 4.335 ;
        RECT 59.235 3.795 59.405 3.965 ;
        RECT 59.975 3.795 60.145 3.965 ;
        RECT 60.715 4.535 60.885 4.705 ;
        RECT 62.565 4.535 62.735 4.705 ;
        RECT 63.305 4.165 63.475 4.335 ;
        RECT 66.895 5.305 67.065 5.475 ;
        RECT 65.525 4.535 65.695 4.705 ;
        RECT 64.045 3.795 64.215 3.965 ;
        RECT 65.525 3.795 65.695 3.965 ;
        RECT 66.635 4.165 66.805 4.335 ;
        RECT 68.895 5.305 69.065 5.475 ;
        RECT 70.215 5.305 70.385 5.475 ;
        RECT 69.225 4.535 69.395 4.705 ;
        RECT 66.635 2.315 66.805 2.485 ;
        RECT 66.935 1.275 67.105 1.445 ;
        RECT 72.235 5.305 72.405 5.475 ;
        RECT 70.705 3.055 70.875 3.225 ;
        RECT 70.705 2.175 70.875 2.345 ;
        RECT 70.265 1.275 70.435 1.445 ;
        RECT 72.185 2.175 72.355 2.345 ;
        RECT 73.295 4.165 73.465 4.335 ;
        RECT 73.595 1.275 73.765 1.445 ;
        RECT 0.775 0.095 0.945 0.265 ;
        RECT 1.145 0.095 1.315 0.265 ;
        RECT 1.515 0.095 1.685 0.265 ;
        RECT 1.885 0.095 2.055 0.265 ;
        RECT 2.255 0.095 2.425 0.265 ;
        RECT 2.625 0.095 2.795 0.265 ;
        RECT 2.995 0.095 3.165 0.265 ;
        RECT 3.365 0.095 3.535 0.265 ;
        RECT 3.735 0.095 3.905 0.265 ;
        RECT 4.105 0.095 4.275 0.265 ;
        RECT 4.475 0.095 4.645 0.265 ;
        RECT 4.845 0.095 5.015 0.265 ;
        RECT 5.585 0.095 5.755 0.265 ;
        RECT 5.955 0.095 6.125 0.265 ;
        RECT 6.325 0.095 6.495 0.265 ;
        RECT 6.695 0.095 6.865 0.265 ;
        RECT 7.065 0.095 7.235 0.265 ;
        RECT 7.435 0.095 7.605 0.265 ;
        RECT 7.805 0.095 7.975 0.265 ;
        RECT 8.175 0.095 8.345 0.265 ;
        RECT 8.915 0.095 9.085 0.265 ;
        RECT 9.285 0.095 9.455 0.265 ;
        RECT 9.655 0.095 9.825 0.265 ;
        RECT 10.025 0.095 10.195 0.265 ;
        RECT 10.395 0.095 10.565 0.265 ;
        RECT 10.765 0.095 10.935 0.265 ;
        RECT 11.135 0.095 11.305 0.265 ;
        RECT 11.505 0.095 11.675 0.265 ;
        RECT 12.245 0.095 12.415 0.265 ;
        RECT 12.615 0.095 12.785 0.265 ;
        RECT 12.985 0.095 13.155 0.265 ;
        RECT 13.355 0.095 13.525 0.265 ;
        RECT 13.725 0.095 13.895 0.265 ;
        RECT 14.095 0.095 14.265 0.265 ;
        RECT 14.465 0.095 14.635 0.265 ;
        RECT 14.835 0.095 15.005 0.265 ;
        RECT 15.575 0.095 15.745 0.265 ;
        RECT 15.945 0.095 16.115 0.265 ;
        RECT 16.315 0.095 16.485 0.265 ;
        RECT 16.685 0.095 16.855 0.265 ;
        RECT 17.055 0.095 17.225 0.265 ;
        RECT 17.425 0.095 17.595 0.265 ;
        RECT 17.795 0.095 17.965 0.265 ;
        RECT 18.165 0.095 18.335 0.265 ;
        RECT 18.905 0.095 19.075 0.265 ;
        RECT 19.275 0.095 19.445 0.265 ;
        RECT 19.645 0.095 19.815 0.265 ;
        RECT 20.015 0.095 20.185 0.265 ;
        RECT 20.385 0.095 20.555 0.265 ;
        RECT 20.755 0.095 20.925 0.265 ;
        RECT 21.125 0.095 21.295 0.265 ;
        RECT 21.495 0.095 21.665 0.265 ;
        RECT 22.235 0.095 22.405 0.265 ;
        RECT 22.605 0.095 22.775 0.265 ;
        RECT 22.975 0.095 23.145 0.265 ;
        RECT 23.345 0.095 23.515 0.265 ;
        RECT 23.715 0.095 23.885 0.265 ;
        RECT 24.085 0.095 24.255 0.265 ;
        RECT 24.455 0.095 24.625 0.265 ;
        RECT 24.825 0.095 24.995 0.265 ;
        RECT 25.195 0.095 25.365 0.265 ;
        RECT 25.565 0.095 25.735 0.265 ;
        RECT 25.935 0.095 26.105 0.265 ;
        RECT 26.305 0.095 26.475 0.265 ;
        RECT 27.045 0.095 27.215 0.265 ;
        RECT 27.415 0.095 27.585 0.265 ;
        RECT 27.785 0.095 27.955 0.265 ;
        RECT 28.155 0.095 28.325 0.265 ;
        RECT 28.525 0.095 28.695 0.265 ;
        RECT 28.895 0.095 29.065 0.265 ;
        RECT 29.265 0.095 29.435 0.265 ;
        RECT 29.635 0.095 29.805 0.265 ;
        RECT 30.375 0.095 30.545 0.265 ;
        RECT 30.745 0.095 30.915 0.265 ;
        RECT 31.115 0.095 31.285 0.265 ;
        RECT 31.485 0.095 31.655 0.265 ;
        RECT 31.855 0.095 32.025 0.265 ;
        RECT 32.225 0.095 32.395 0.265 ;
        RECT 32.595 0.095 32.765 0.265 ;
        RECT 32.965 0.095 33.135 0.265 ;
        RECT 33.705 0.095 33.875 0.265 ;
        RECT 34.075 0.095 34.245 0.265 ;
        RECT 34.445 0.095 34.615 0.265 ;
        RECT 34.815 0.095 34.985 0.265 ;
        RECT 35.185 0.095 35.355 0.265 ;
        RECT 35.555 0.095 35.725 0.265 ;
        RECT 35.925 0.095 36.095 0.265 ;
        RECT 36.295 0.095 36.465 0.265 ;
        RECT 37.035 0.095 37.205 0.265 ;
        RECT 37.405 0.095 37.575 0.265 ;
        RECT 37.775 0.095 37.945 0.265 ;
        RECT 38.145 0.095 38.315 0.265 ;
        RECT 38.515 0.095 38.685 0.265 ;
        RECT 38.885 0.095 39.055 0.265 ;
        RECT 39.255 0.095 39.425 0.265 ;
        RECT 39.625 0.095 39.795 0.265 ;
        RECT 40.365 0.095 40.535 0.265 ;
        RECT 40.735 0.095 40.905 0.265 ;
        RECT 41.105 0.095 41.275 0.265 ;
        RECT 41.475 0.095 41.645 0.265 ;
        RECT 41.845 0.095 42.015 0.265 ;
        RECT 42.215 0.095 42.385 0.265 ;
        RECT 42.585 0.095 42.755 0.265 ;
        RECT 42.955 0.095 43.125 0.265 ;
        RECT 43.695 0.095 43.865 0.265 ;
        RECT 44.065 0.095 44.235 0.265 ;
        RECT 44.435 0.095 44.605 0.265 ;
        RECT 44.805 0.095 44.975 0.265 ;
        RECT 45.175 0.095 45.345 0.265 ;
        RECT 45.545 0.095 45.715 0.265 ;
        RECT 45.915 0.095 46.085 0.265 ;
        RECT 46.285 0.095 46.455 0.265 ;
        RECT 46.655 0.095 46.825 0.265 ;
        RECT 47.025 0.095 47.195 0.265 ;
        RECT 47.395 0.095 47.565 0.265 ;
        RECT 47.765 0.095 47.935 0.265 ;
        RECT 48.505 0.095 48.675 0.265 ;
        RECT 48.875 0.095 49.045 0.265 ;
        RECT 49.245 0.095 49.415 0.265 ;
        RECT 49.615 0.095 49.785 0.265 ;
        RECT 49.985 0.095 50.155 0.265 ;
        RECT 50.355 0.095 50.525 0.265 ;
        RECT 50.725 0.095 50.895 0.265 ;
        RECT 51.095 0.095 51.265 0.265 ;
        RECT 51.835 0.095 52.005 0.265 ;
        RECT 52.205 0.095 52.375 0.265 ;
        RECT 52.575 0.095 52.745 0.265 ;
        RECT 52.945 0.095 53.115 0.265 ;
        RECT 53.315 0.095 53.485 0.265 ;
        RECT 53.685 0.095 53.855 0.265 ;
        RECT 54.055 0.095 54.225 0.265 ;
        RECT 54.425 0.095 54.595 0.265 ;
        RECT 55.165 0.095 55.335 0.265 ;
        RECT 55.535 0.095 55.705 0.265 ;
        RECT 55.905 0.095 56.075 0.265 ;
        RECT 56.275 0.095 56.445 0.265 ;
        RECT 56.645 0.095 56.815 0.265 ;
        RECT 57.015 0.095 57.185 0.265 ;
        RECT 57.385 0.095 57.555 0.265 ;
        RECT 57.755 0.095 57.925 0.265 ;
        RECT 58.495 0.095 58.665 0.265 ;
        RECT 58.865 0.095 59.035 0.265 ;
        RECT 59.235 0.095 59.405 0.265 ;
        RECT 59.605 0.095 59.775 0.265 ;
        RECT 59.975 0.095 60.145 0.265 ;
        RECT 60.345 0.095 60.515 0.265 ;
        RECT 60.715 0.095 60.885 0.265 ;
        RECT 61.085 0.095 61.255 0.265 ;
        RECT 61.825 0.095 61.995 0.265 ;
        RECT 62.195 0.095 62.365 0.265 ;
        RECT 62.565 0.095 62.735 0.265 ;
        RECT 62.935 0.095 63.105 0.265 ;
        RECT 63.305 0.095 63.475 0.265 ;
        RECT 63.675 0.095 63.845 0.265 ;
        RECT 64.045 0.095 64.215 0.265 ;
        RECT 64.415 0.095 64.585 0.265 ;
        RECT 65.155 0.095 65.325 0.265 ;
        RECT 65.525 0.095 65.695 0.265 ;
        RECT 65.895 0.095 66.065 0.265 ;
        RECT 66.265 0.095 66.435 0.265 ;
        RECT 66.635 0.095 66.805 0.265 ;
        RECT 67.005 0.095 67.175 0.265 ;
        RECT 67.375 0.095 67.545 0.265 ;
        RECT 67.745 0.095 67.915 0.265 ;
        RECT 68.485 0.095 68.655 0.265 ;
        RECT 68.855 0.095 69.025 0.265 ;
        RECT 69.225 0.095 69.395 0.265 ;
        RECT 69.595 0.095 69.765 0.265 ;
        RECT 69.965 0.095 70.135 0.265 ;
        RECT 70.335 0.095 70.505 0.265 ;
        RECT 70.705 0.095 70.875 0.265 ;
        RECT 71.075 0.095 71.245 0.265 ;
        RECT 71.815 0.095 71.985 0.265 ;
        RECT 72.185 0.095 72.355 0.265 ;
        RECT 72.555 0.095 72.725 0.265 ;
        RECT 72.925 0.095 73.095 0.265 ;
        RECT 73.295 0.095 73.465 0.265 ;
        RECT 73.665 0.095 73.835 0.265 ;
        RECT 74.035 0.095 74.205 0.265 ;
        RECT 74.405 0.095 74.575 0.265 ;
      LAYER met1 ;
        RECT 66.865 5.475 67.095 5.505 ;
        RECT 68.865 5.475 69.095 5.505 ;
        RECT 70.185 5.475 70.415 5.505 ;
        RECT 72.205 5.475 72.435 5.505 ;
        RECT 66.835 5.305 69.125 5.475 ;
        RECT 70.155 5.305 72.465 5.475 ;
        RECT 66.865 5.275 67.095 5.305 ;
        RECT 68.865 5.275 69.095 5.305 ;
        RECT 70.185 5.275 70.415 5.305 ;
        RECT 72.205 5.275 72.435 5.305 ;
        RECT 60.685 4.705 60.915 4.735 ;
        RECT 62.535 4.705 62.765 4.735 ;
        RECT 65.495 4.705 65.725 4.735 ;
        RECT 69.195 4.705 69.425 4.735 ;
        RECT 60.655 4.535 62.795 4.705 ;
        RECT 65.465 4.535 69.455 4.705 ;
        RECT 60.685 4.505 60.915 4.535 ;
        RECT 62.535 4.505 62.765 4.535 ;
        RECT 65.495 4.505 65.725 4.535 ;
        RECT 69.195 4.505 69.425 4.535 ;
        RECT 1.485 4.335 1.715 4.365 ;
        RECT 10.365 4.335 10.595 4.365 ;
        RECT 14.435 4.335 14.665 4.365 ;
        RECT 20.355 4.335 20.585 4.365 ;
        RECT 22.945 4.335 23.175 4.365 ;
        RECT 31.825 4.335 32.055 4.365 ;
        RECT 35.895 4.335 36.125 4.365 ;
        RECT 41.815 4.335 42.045 4.365 ;
        RECT 44.405 4.335 44.635 4.365 ;
        RECT 53.285 4.335 53.515 4.365 ;
        RECT 57.355 4.335 57.585 4.365 ;
        RECT 63.275 4.335 63.505 4.365 ;
        RECT 66.605 4.335 66.835 4.365 ;
        RECT 73.265 4.335 73.495 4.365 ;
        RECT 1.455 4.165 20.615 4.335 ;
        RECT 22.915 4.165 42.075 4.335 ;
        RECT 44.375 4.165 63.535 4.335 ;
        RECT 66.575 4.165 73.525 4.335 ;
        RECT 1.485 4.135 1.715 4.165 ;
        RECT 10.365 4.135 10.595 4.165 ;
        RECT 14.435 4.135 14.665 4.165 ;
        RECT 20.355 4.135 20.585 4.165 ;
        RECT 22.945 4.135 23.175 4.165 ;
        RECT 31.825 4.135 32.055 4.165 ;
        RECT 35.895 4.135 36.125 4.165 ;
        RECT 41.815 4.135 42.045 4.165 ;
        RECT 44.405 4.135 44.635 4.165 ;
        RECT 53.285 4.135 53.515 4.165 ;
        RECT 57.355 4.135 57.585 4.165 ;
        RECT 63.275 4.135 63.505 4.165 ;
        RECT 66.605 4.135 66.835 4.165 ;
        RECT 73.265 4.135 73.495 4.165 ;
        RECT 4.445 3.965 4.675 3.995 ;
        RECT 6.295 3.965 6.525 3.995 ;
        RECT 16.285 3.965 16.515 3.995 ;
        RECT 17.765 3.965 17.995 3.995 ;
        RECT 19.615 3.965 19.845 3.995 ;
        RECT 25.905 3.965 26.135 3.995 ;
        RECT 27.755 3.965 27.985 3.995 ;
        RECT 37.745 3.965 37.975 3.995 ;
        RECT 39.225 3.965 39.455 3.995 ;
        RECT 41.075 3.965 41.305 3.995 ;
        RECT 47.365 3.965 47.595 3.995 ;
        RECT 49.215 3.965 49.445 3.995 ;
        RECT 59.205 3.965 59.435 3.995 ;
        RECT 59.945 3.965 60.175 3.995 ;
        RECT 64.015 3.965 64.245 3.995 ;
        RECT 65.495 3.965 65.725 3.995 ;
        RECT 4.415 3.795 16.545 3.965 ;
        RECT 17.735 3.795 19.875 3.965 ;
        RECT 25.875 3.795 38.005 3.965 ;
        RECT 39.195 3.795 41.335 3.965 ;
        RECT 47.335 3.795 59.465 3.965 ;
        RECT 59.915 3.795 65.755 3.965 ;
        RECT 4.445 3.765 4.675 3.795 ;
        RECT 6.295 3.765 6.525 3.795 ;
        RECT 16.285 3.765 16.515 3.795 ;
        RECT 17.765 3.765 17.995 3.795 ;
        RECT 19.615 3.765 19.845 3.795 ;
        RECT 25.905 3.765 26.135 3.795 ;
        RECT 27.755 3.765 27.985 3.795 ;
        RECT 37.745 3.765 37.975 3.795 ;
        RECT 39.225 3.765 39.455 3.795 ;
        RECT 41.075 3.765 41.305 3.795 ;
        RECT 47.365 3.765 47.595 3.795 ;
        RECT 49.215 3.765 49.445 3.795 ;
        RECT 59.205 3.765 59.435 3.795 ;
        RECT 59.945 3.765 60.175 3.795 ;
        RECT 64.015 3.765 64.245 3.795 ;
        RECT 65.495 3.765 65.725 3.795 ;
        RECT 3.705 3.595 3.935 3.625 ;
        RECT 7.775 3.595 8.005 3.625 ;
        RECT 9.625 3.595 9.855 3.625 ;
        RECT 11.105 3.595 11.335 3.625 ;
        RECT 12.955 3.595 13.185 3.625 ;
        RECT 25.165 3.595 25.395 3.625 ;
        RECT 29.235 3.595 29.465 3.625 ;
        RECT 31.085 3.595 31.315 3.625 ;
        RECT 32.565 3.595 32.795 3.625 ;
        RECT 34.415 3.595 34.645 3.625 ;
        RECT 46.625 3.595 46.855 3.625 ;
        RECT 50.695 3.595 50.925 3.625 ;
        RECT 52.545 3.595 52.775 3.625 ;
        RECT 54.025 3.595 54.255 3.625 ;
        RECT 55.875 3.595 56.105 3.625 ;
        RECT 3.675 3.425 9.885 3.595 ;
        RECT 11.075 3.425 13.215 3.595 ;
        RECT 25.135 3.425 31.345 3.595 ;
        RECT 32.535 3.425 34.675 3.595 ;
        RECT 46.595 3.425 52.805 3.595 ;
        RECT 53.995 3.425 56.135 3.595 ;
        RECT 3.705 3.395 3.935 3.425 ;
        RECT 7.775 3.395 8.005 3.425 ;
        RECT 9.625 3.395 9.855 3.425 ;
        RECT 11.105 3.395 11.335 3.425 ;
        RECT 12.955 3.395 13.185 3.425 ;
        RECT 25.165 3.395 25.395 3.425 ;
        RECT 29.235 3.395 29.465 3.425 ;
        RECT 31.085 3.395 31.315 3.425 ;
        RECT 32.565 3.395 32.795 3.425 ;
        RECT 34.415 3.395 34.645 3.425 ;
        RECT 46.625 3.395 46.855 3.425 ;
        RECT 50.695 3.395 50.925 3.425 ;
        RECT 52.545 3.395 52.775 3.425 ;
        RECT 54.025 3.395 54.255 3.425 ;
        RECT 55.875 3.395 56.105 3.425 ;
        RECT 17.025 3.225 17.255 3.255 ;
        RECT 21.095 3.225 21.325 3.255 ;
        RECT 70.675 3.225 70.905 3.255 ;
        RECT 16.995 3.055 70.935 3.225 ;
        RECT 17.025 3.025 17.255 3.055 ;
        RECT 21.095 3.025 21.325 3.055 ;
        RECT 70.675 3.025 70.905 3.055 ;
        RECT 38.485 2.485 38.715 2.515 ;
        RECT 42.555 2.485 42.785 2.515 ;
        RECT 66.605 2.485 66.835 2.515 ;
        RECT 38.455 2.315 66.865 2.485 ;
        RECT 70.675 2.345 70.905 2.375 ;
        RECT 72.155 2.345 72.385 2.375 ;
        RECT 38.485 2.285 38.715 2.315 ;
        RECT 42.555 2.285 42.785 2.315 ;
        RECT 66.605 2.285 66.835 2.315 ;
        RECT 70.645 2.175 72.415 2.345 ;
        RECT 70.675 2.145 70.905 2.175 ;
        RECT 72.155 2.145 72.385 2.175 ;
  END
END TMRDFFQNX1
END LIBRARY

